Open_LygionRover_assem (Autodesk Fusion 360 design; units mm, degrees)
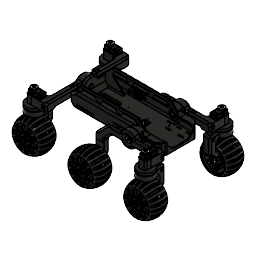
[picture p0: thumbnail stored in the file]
description: Part Number
part number: LygionRover
part number: MSBR-12
part number: MSBR-10
part number: MSBR-9
part number: MSBR-8
part number: MSBR-7
part number: MSBR-6
part number: MSBR-5
part number: MSBR-4
part number: MSBR-3
part number: MSBR-2
part number: MSBR-1
part number: SCS15_ASM_ASM
part number: SC-1500-C024
part number: 3DP_Wheel_servo_holder
part number: MF84ZZ
part number: LOCK-NUT-M3
part number: 3DP_Wheel
part number: BEARING-51105
base_feature "Base Feature1"
base_feature "Base Feature1"
base_feature "Base Feature1"
base_feature "Base Feature1"
base_feature "Base Feature1"
base_feature "Base Feature1"
base_feature "Base Feature1"
base_feature "Base Feature1"
base_feature "Base Feature1"
base_feature "Base Feature1"
base_feature "Base Feature1"
base_feature "Base Feature1"
base_feature "Base Feature1"
base_feature "Base Feature1"
base_feature "Base Feature1"
base_feature "Base Feature1"
base_feature "Base Feature1"
base_feature "Base Feature1"
base_feature "Base Feature1"
base_feature "Base Feature1"
base_feature "Base Feature1"
base_feature "Base Feature1"
base_feature "Base Feature1"
base_feature "Base Feature1"
base_feature "Base Feature1"
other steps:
create_component "CreateComponent1"
create_component "CreateComponent1"
create_component "CreateComponent1"
create_component "CreateComponent2"
create_component "CreateComponent3"
create_component "CreateComponent4"
create_component "CreateComponent5"
create_component "CreateComponent6"
create_component "CreateComponent7"
create_component "CreateComponent8"
create_component "CreateComponent9"
create_component "CreateComponent10"
create_component "CreateComponent11"
create_component "CreateComponent2"
create_component "CreateComponent1"
create_component "CreateComponent3"
create_component "CreateComponent4"
create_component "CreateComponent5"
create_component "CreateComponent6"
create_component "CreateComponent1"
create_component "CreateComponent7"
create_component "CreateComponent8"
create_component "CreateComponent1"
create_component "CreateComponent9"
create_component "CreateComponent1"
create_component "CreateComponent1"
create_component "CreateComponent10"
create_component "CreateComponent1"
create_component "CreateComponent11"
create_component "CreateComponent12"
create_component "CreateComponent1"
create_component "CreateComponent13"
create_component "CreateComponent1"
create_component "CreateComponent14"
create_component "CreateComponent15"
create_component "CreateComponent1"
create_component "CreateComponent16"
create_component "CreateComponent17"
create_component "CreateComponent1"
create_component "CreateComponent18"
create_component "CreateComponent1"
create_component "CreateComponent19"
create_component "CreateComponent1"
create_component "CreateComponent20"
create_component "CreateComponent1"
create_component "CreateComponent21"
create_component "CreateComponent1"
create_component "CreateComponent22"
create_component "CreateComponent1"
create_component "CreateComponent23"
create_component "CreateComponent1"
create_component "CreateComponent24"
create_component "CreateComponent1"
